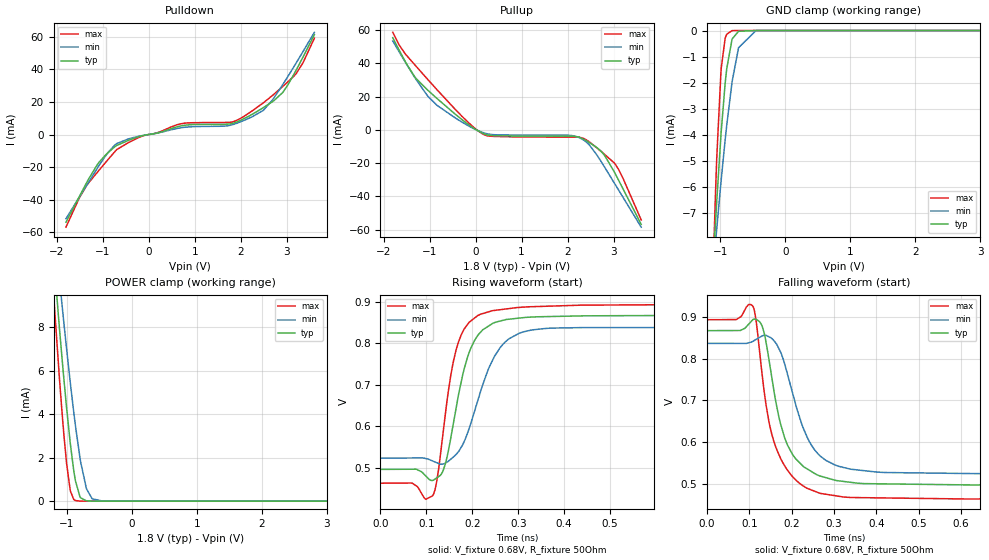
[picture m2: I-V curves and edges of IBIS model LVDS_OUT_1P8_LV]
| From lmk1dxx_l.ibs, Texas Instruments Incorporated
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|   LVDS_OUT_1P8_LV Model
[Model]   LVDS_OUT_1P8_LV
Model_type   Output
Polarity   Non-Inverting
Vmeas = 0.68
Vref = 0.68
Cref = 2pF
Rref = 50
|   typ   min   max
C_comp   0.89pF   0.82pF   0.98pF
[Rac]   50   NA   NA
[Cac]   2p   NA   NA
[Voltage Range]   1.8   1.71   1.89
[Temperature Range]   45   150   -40
[Pullup Reference]   1.8   1.71   1.89
[Pulldown Reference]   0   0   0
[Power Clamp Reference]   1.8   1.71   1.89
[GND Clamp Reference]   0   0   0
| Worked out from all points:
|   slope of the pulldown table from 0 to 0.27 V, typ, clamps not added: 171 ohm
|   slope of the pullup table from 0 to 0.27 V, typ, clamps not added: 79.3 ohm
|   GND clamp passes 1 mA (typ) near -0.87 V on its own axis
|   POWER clamp passes 1 mA (typ) near -0.87 V on its own axis
|   falling waveform, V_fixture 0.68V, R_fixture 50Ohm: 20-80 % time 55.1ps typ, 64.4ps min, 54.8ps max; typ from 0.867 V to 0.496 V
|   rising waveform, V_fixture 0.68V, R_fixture 50Ohm: 20-80 % time 46ps typ, 61.2ps min, 38.8ps max; typ from 0.496 V to 0.867 V
[Pulldown]
|   Voltage   I(typ)   I(min)   I(max)
-1.8V     -53.93mA   -51.78mA   -56.96mA
-1.513V   -38.38mA   -38.7mA    -39.19mA
-1.113V   -18.29mA   -20.5mA    -23.07mA
-696.8mV  -6.741mA   -5.575mA   -9.302mA
-203.2mV  -1.213mA   -1.012mA   -1.69mA
700.2mV   5.276mA    4.137mA    6.61mA
1.85V     7.08mA     6.306mA    8.011mA
2.49V     16.48mA    14.86mA    19.46mA
2.913V    25.87mA    30.69mA    29.54mA
3.204V    39.56mA    43.99mA    37.4mA
3.352V    47.54mA    50.96mA    44.06mA
3.6V      61.38mA    62.82mA    59.2mA
[GND Clamp]
|   Voltage   I(typ)   I(min)   I(max)
-1.8V     -47.22mA   -32.28mA   -90.43mA
-1.103V   -8.782mA   -9.069mA   -8.722mA
-1.072V   -7.372mA   -8.153mA   -6.225mA
-1.053V   -6.556mA   -7.61mA    -4.893mA
-988.9mV  -4.055mA   -5.855mA   -1.636mA
-982.4mV  -3.827mA   -5.684mA   -1.42mA
-922.5mV  -2.008mA   -4.177mA   -294.7uA
-899.8mV  -1.477mA   -3.648mA   -144.9uA
-818.3mV  -346uA     -1.998mA   -5.222uA
-717.3mV  -29.3uA    -659.5uA   -36.6nA
-450mV    -2.385nA   -3.724uA   -4.984pA
3.6V      0A         0A         0A
[Pullup]
|   Voltage   I(typ)   I(min)   I(max)
-1.8V     55.45mA    53.49mA    58.68mA
-1.659V   47.85mA    46.88mA    50.96mA
-1.324V   31.98mA    31.64mA    39.21mA
-1.036V   23.79mA    20.16mA    30.22mA
-450mV    9.602mA    7.326mA    12.55mA
160.7mV   -2.134mA   -1.621mA   -2.55mA
2.08V     -3.823mA   -3.39mA    -4.347mA
2.353V    -5.675mA   -6.182mA   -5.156mA
2.724V    -12.74mA   -18.85mA   -12.9mA
3.039V    -26.61mA   -33.09mA   -20.79mA
3.207V    -35.65mA   -40.72mA   -29.36mA
3.6V      -56.88mA   -58.55mA   -54.19mA
[POWER Clamp]
|   Voltage   I(typ)   I(min)   I(max)
-1.8V     35.35mA    33.02mA    38.41mA
-1.235V   12.58mA    14.14mA    11.07mA
-1.108V   7.901mA    10.18mA    5.58mA
-1.068V   6.535mA    8.999mA    4.045mA
-1V       4.324mA    7.032mA    1.764mA
-945.7mV  2.747mA    5.536mA    547.3uA
-890.1mV  1.424mA    4.11mA     81.35uA
-863.6mV  938uA      3.477mA    28.21uA
-793.4mV  199.1uA    1.989mA    1.463uA
-694.6mV  11.18uA    577.1uA    13.82nA
-607.7mV  708.9nA    109.9uA    193pA
3.6V      0A         0A         0A
[Ramp]
R_load = 50
|   typ   min   max
dV/dt_r   0.222702/4.5842e-11   0.188228/6.08617e-11   0.258334/3.86844e-11
dV/dt_f   0.222822/5.5174e-11   0.188544/6.42638e-11   0.258423/5.48415e-11
[Falling Waveform]
V_fixture = 0.68V
V_fixture_min = 0.68V
V_fixture_max = 0.68V
R_fixture = 50Ohm
C_fixture = 0F
|   Time   V(typ)   V(min)   V(max)
0s        866.9mV    836.3mV    893mV
107.9ps   893mV      841.1mV    925.9mV
116ps     894.2mV    846mV      888.1mV
134.8ps   861.5mV    855.5mV    721.2mV
150.4ps   770.2mV    849.9mV    628.4mV
173.1ps   644.9mV    816.4mV    561.6mV
201ps     571.4mV    720.7mV    517.7mV
242.5ps   531.5mV    599.2mV    486.3mV
323ps     505.2mV    538.6mV    467.8mV
5ns       495.5mV    522.1mV    462.3mV
[Rising Waveform]
V_fixture = 0.68V
V_fixture_min = 0.68V
V_fixture_max = 0.68V
R_fixture = 50Ohm
C_fixture = 0F
|   Time   V(typ)   V(min)   V(max)
0s        495.7mV    522.6mV    462.3mV
113.3ps   468.9mV    516.1mV    431.7mV
122.4ps   474.9mV    511.9mV    464.6mV
141.5ps   509mV      510.8mV    628.6mV
157.4ps   596.8mV    524.1mV    747.1mV
176ps     706.5mV    549.1mV    819.7mV
213.4ps   820.4mV    666.3mV    867mV
248.3ps   849.2mV    768mV      878.6mV
297.4ps   859.6mV    820.7mV    885.5mV
5ns       866.8mV    836.3mV    892.9mV
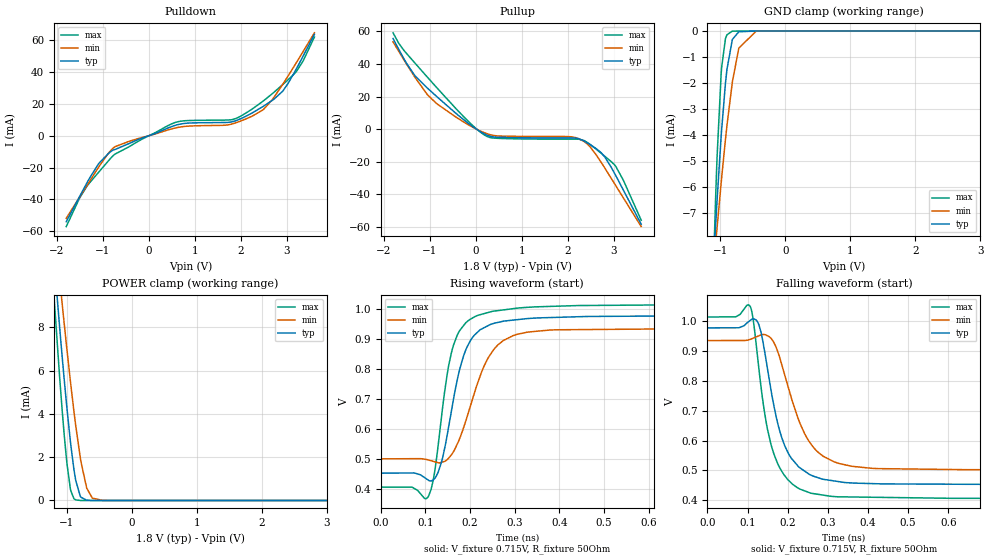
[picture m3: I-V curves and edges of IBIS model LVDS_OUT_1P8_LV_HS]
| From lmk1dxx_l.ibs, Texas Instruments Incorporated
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|   LVDS_OUT_1P8_LV_HS Model
[Model]   LVDS_OUT_1P8_LV_HS
Model_type   Output
Polarity   Non-Inverting
Vmeas = 0.715
Vref = 0.715
Cref = 2pF
Rref = 50
|   typ   min   max
C_comp   0.89pF   0.82pF   0.98pF
[Rac]   50   NA   NA
[Cac]   2p   NA   NA
[Voltage Range]   1.8   1.71   1.89
[Temperature Range]   45   150   -40
[Pullup Reference]   1.8   1.71   1.89
[Pulldown Reference]   0   0   0
[Power Clamp Reference]   1.8   1.71   1.89
[GND Clamp Reference]   0   0   0
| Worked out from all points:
|   slope of the pulldown table from 0 to 0.27 V, typ, clamps not added: 89.3 ohm
|   slope of the pullup table from 0 to 0.27 V, typ, clamps not added: 64.1 ohm
|   GND clamp passes 1 mA (typ) near -0.87 V on its own axis
|   POWER clamp passes 1 mA (typ) near -0.87 V on its own axis
|   falling waveform, V_fixture 0.715V, R_fixture 50Ohm: 20-80 % time 56.1ps typ, 72.8ps min, 49.8ps max; typ from 0.977 V to 0.452 V
|   rising waveform, V_fixture 0.715V, R_fixture 50Ohm: 20-80 % time 46.9ps typ, 63.8ps min, 38.9ps max; typ from 0.452 V to 0.977 V
[Pulldown]
|   Voltage   I(typ)   I(min)   I(max)
-1.8V     -53.93mA   -51.79mA   -56.99mA
-1.513V   -38.38mA   -38.71mA   -39.32mA
-1.111V   -18.25mA   -20.44mA   -23.47mA
-874.4mV  -10.97mA   -10.72mA   -15.5mA
-733.5mV  -8.614mA   -6.853mA   -11.47mA
546.8mV   6.25mA     4.655mA    8.021mA
1.85V     9.028mA    7.704mA    10.37mA
2.487V    18.4mA     16.28mA    21.72mA
2.913V    27.97mA    32.28mA    32.09mA
3.206V    41.84mA    45.73mA    40.15mA
3.354V    49.81mA    52.69mA    46.79mA
3.6V      63.55mA    64.48mA    61.82mA
[GND Clamp]
|   Voltage   I(typ)   I(min)   I(max)
-1.8V     -47.22mA   -32.28mA   -90.43mA
-1.103V   -8.782mA   -9.069mA   -8.722mA
-1.072V   -7.372mA   -8.153mA   -6.225mA
-1.053V   -6.556mA   -7.61mA    -4.893mA
-988.9mV  -4.055mA   -5.855mA   -1.636mA
-982.4mV  -3.827mA   -5.684mA   -1.42mA
-922.5mV  -2.008mA   -4.177mA   -294.7uA
-899.8mV  -1.477mA   -3.648mA   -144.9uA
-818.3mV  -346uA     -1.998mA   -5.222uA
-717.3mV  -29.3uA    -659.5uA   -36.6nA
-450mV    -2.385nA   -3.724uA   -4.984pA
3.6V      0A         0A         0A
[Pullup]
|   Voltage   I(typ)   I(min)   I(max)
-1.8V     55.68mA    53.63mA    59.18mA
-1.68V    49.25mA    48.02mA    52.93mA
-1.337V   33.31mA    32.46mA    41.03mA
-1.049V   25.14mA    21.07mA    31.82mA
-450mV    10.15mA    7.757mA    13.17mA
220.7mV   -3.371mA   -2.556mA   -4.146mA
2.08V     -5.401mA   -4.718mA   -6.146mA
2.354V    -7.281mA   -7.536mA   -6.981mA
2.725V    -14.37mA   -20.23mA   -14.76mA
3.046V    -28.57mA   -34.74mA   -22.89mA
3.213V    -37.54mA   -42.29mA   -31.5mA
3.6V      -58.47mA   -59.88mA   -56mA
[POWER Clamp]
|   Voltage   I(typ)   I(min)   I(max)
-1.8V     35.35mA    33.02mA    38.41mA
-1.235V   12.58mA    14.14mA    11.07mA
-1.108V   7.901mA    10.18mA    5.58mA
-1.068V   6.535mA    8.999mA    4.045mA
-1V       4.324mA    7.032mA    1.764mA
-945.7mV  2.747mA    5.536mA    547.3uA
-890.1mV  1.424mA    4.11mA     81.35uA
-863.6mV  938uA      3.477mA    28.21uA
-793.4mV  199.1uA    1.989mA    1.463uA
-694.6mV  11.18uA    577.1uA    13.82nA
-607.7mV  708.9nA    109.9uA    193pA
3.6V      0A         0A         0A
[Ramp]
R_load = 50
|   typ   min   max
dV/dt_r   0.314951/4.69062e-11   0.260917/6.35929e-11   0.364386/3.85733e-11
dV/dt_f   0.315158/5.61369e-11   0.26153/7.2216e-11   0.364553/4.98086e-11
[Falling Waveform]
V_fixture = 0.715V
V_fixture_min = 0.715V
V_fixture_max = 0.715V
R_fixture = 50Ohm
C_fixture = 0F
|   Time   V(typ)   V(min)   V(max)
0s        976.8mV    934.5mV    1.013V
106.2ps   1.001V     938.1mV    1.049V
114.5ps   1.007V     942.7mV    998.9mV
133ps     964.8mV    952.9mV    785.2mV
149.6ps   840.3mV    950.3mV    637.8mV
173.9ps   664.1mV    902.3mV    526.3mV
200.9ps   558.7mV    780.1mV    468.3mV
241.9ps   498mV      623.7mV    431.8mV
307.9ps   466.4mV    534.1mV    413.4mV
5ns       451.6mV    498.6mV    405.4mV
[Rising Waveform]
V_fixture = 0.715V
V_fixture_min = 0.715V
V_fixture_max = 0.715V
R_fixture = 50Ohm
C_fixture = 0F
|   Time   V(typ)   V(min)   V(max)
0s        451.8mV    499.5mV    405.5mV
104.7ps   430.6mV    496.7mV    369.9mV
118.9ps   430.9mV    490.8mV    438.4mV
135.6ps   485.4mV    487.8mV    631.5mV
152.2ps   606.5mV    502.2mV    810.1mV
171.1ps   759.8mV    547.8mV    910.7mV
200.9ps   893.9mV    675.8mV    965.2mV
241.9ps   944.6mV    839.2mV    988mV
307.9ps   964mV      915.5mV    1.002V
5ns       976.7mV    934.4mV    1.013V
